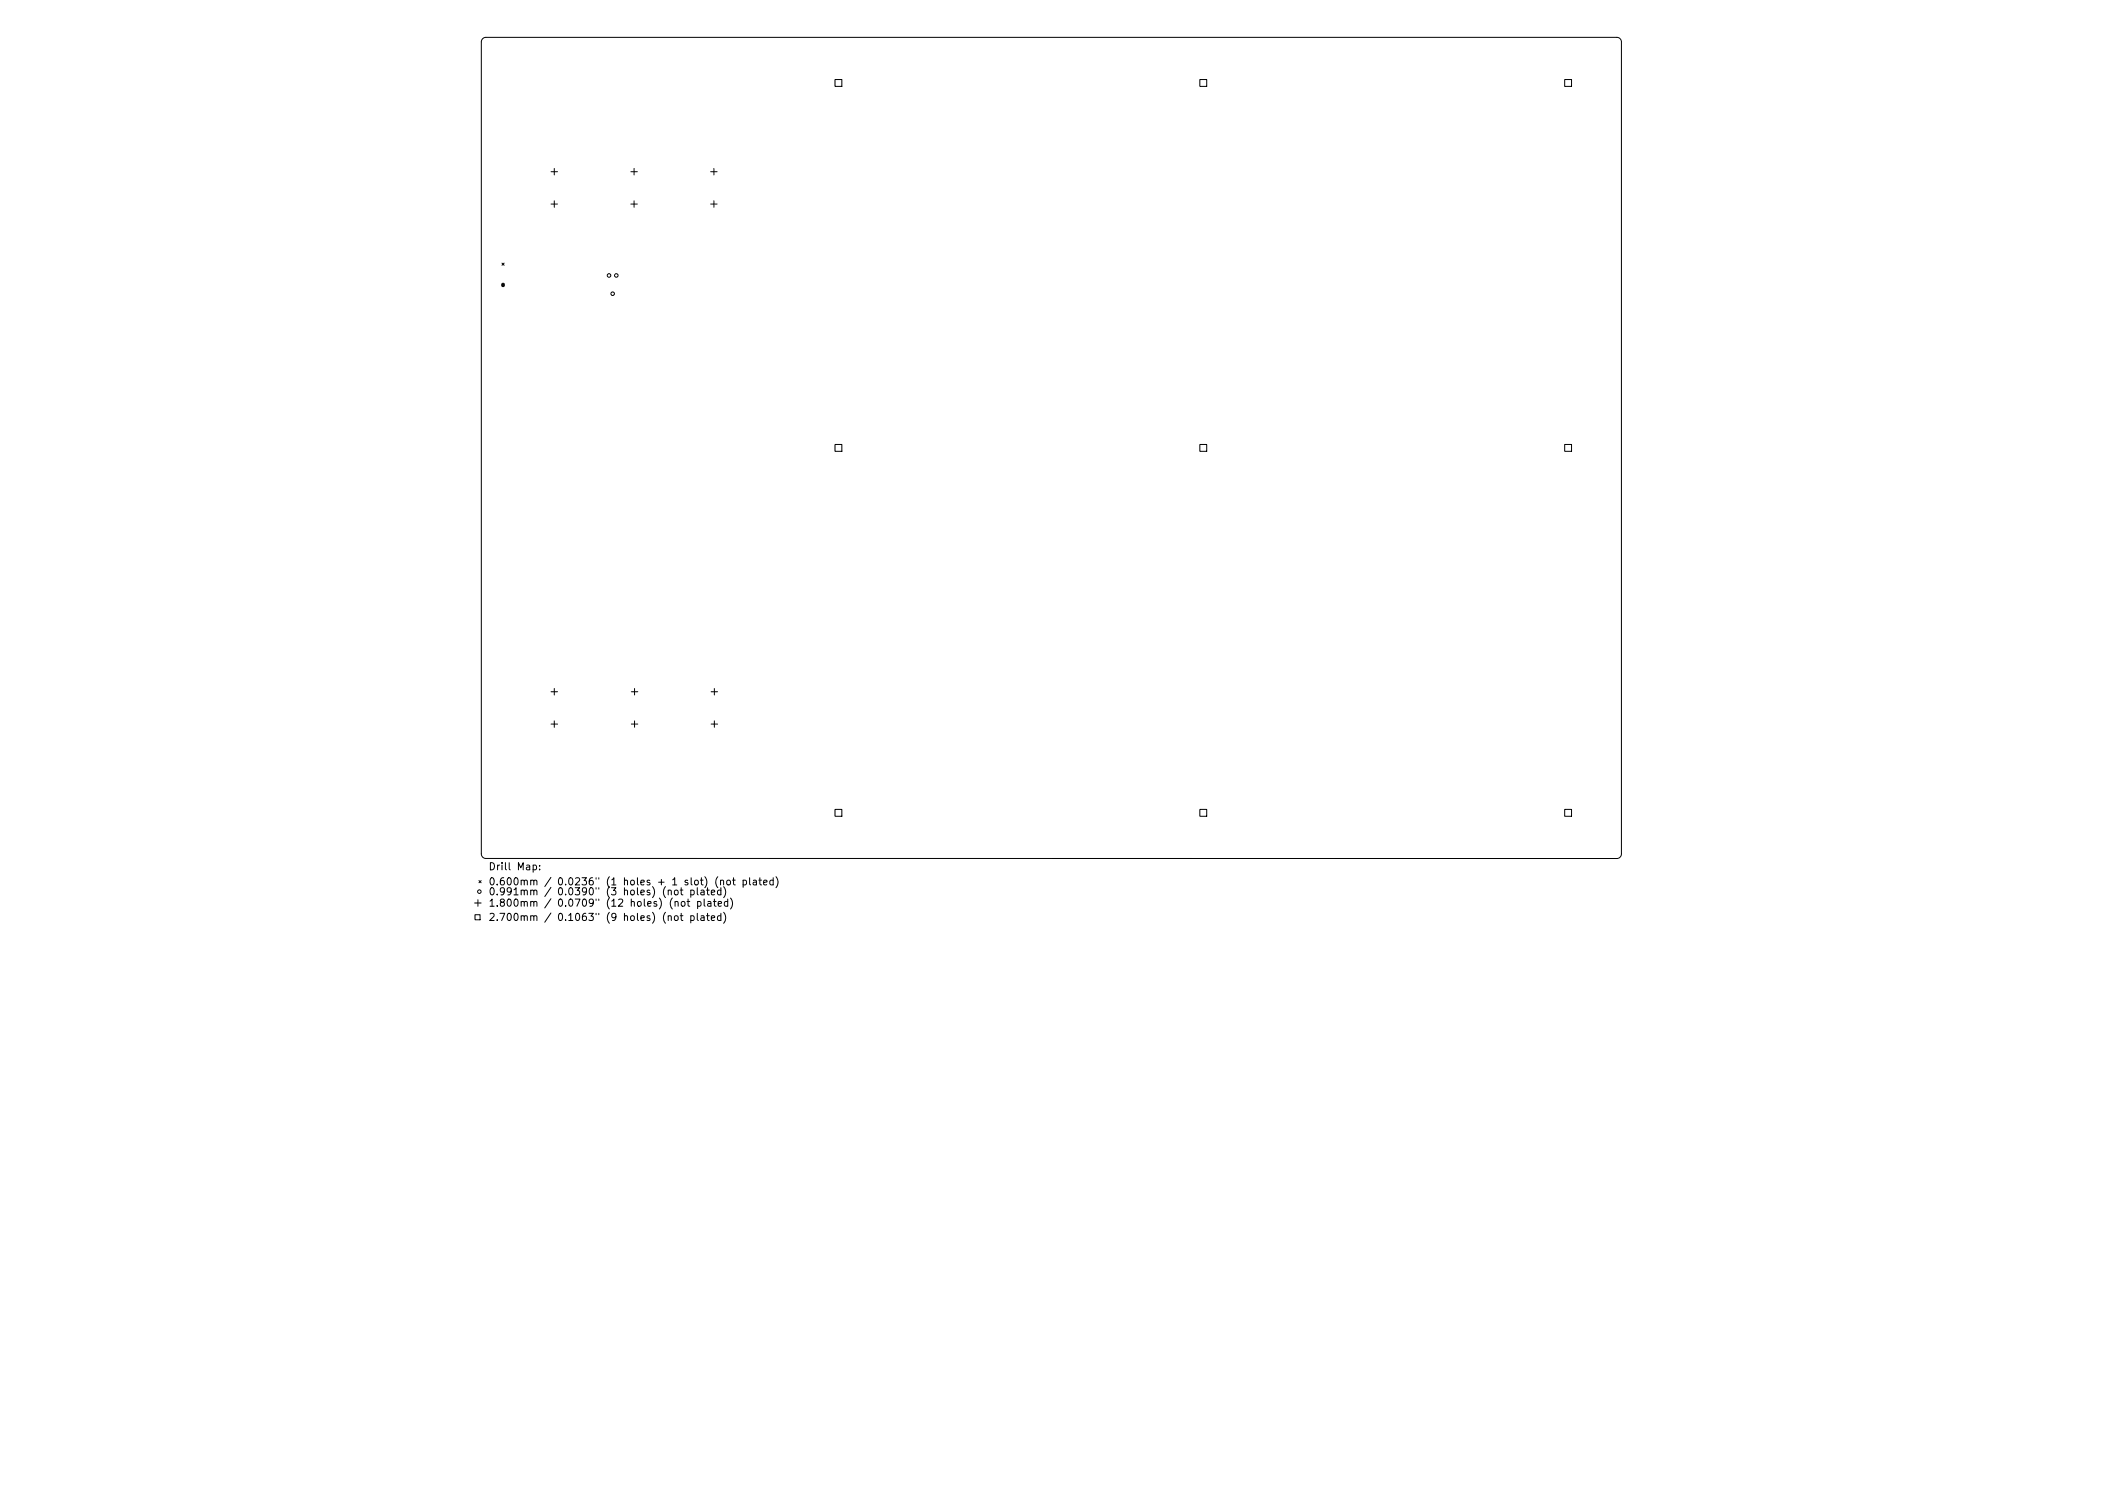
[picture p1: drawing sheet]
<svg xmlns="http://www.w3.org/2000/svg" width="297mm" height="210mm" viewBox="0 0 297 210" stroke-linecap="round" stroke-linejoin="round" font-family="sans-serif">
<defs><g id="words">
<g font-size="1.4">
<text x="69" y="122.9">Drill Map:</text>
<text x="69" y="125">0.600mm / 0.0236&quot; (1 holes + 1 slot) (not plated)</text>
<text x="69" y="126.4">0.991mm / 0.0390&quot; (3 holes) (not plated)</text>
<text x="69" y="128">1.800mm / 0.0709&quot; (12 holes) (not plated)</text>
<text x="69" y="130">2.700mm / 0.1063&quot; (9 holes) (not plated)</text>
</g>
</g></defs>
<g fill="none" stroke="#000" stroke-width=".14">
<path d="M68.2 5.5l.4-.2h159.8a.64 .64 0 0 1 .6 .6v114.7a.65 .65 0 0 1-.6 .6h-159.8a.64 .64 0 0 1-.6-.6v-114.7zM117.9 11.2h1v1h-1zM169.5 11.2h.9v1h-.9zM221 11.2h1v1h-1zM70.9 37.2l.3 .3M71.2 37.2l-.3 .3M77.8 24.2h.9M77.8 28.8h.9M78.3 23.8v.9M78.3 28.4v.9M89.1 24.2h.9M89.1 28.8h.9"/>
<path d="M89.6 23.8v.9M89.6 28.4v.9M100.4 24.2h.9M100.4 28.8h.9M100.8 23.8v.9M100.8 28.4v.9M70.9 40.1l.3 .3M70.9 40l.3 .1-.1 .4-.2-.1zM71.2 40.1l-.3 .3M117.9 62.8h1v.9h-1zM169.5 62.8h.9v.9h-.9zM221 62.8h1v.9h-1z"/>
<path d="M77.8 97.7h.9M78.3 97.2v.9M89.2 97.7h.9M89.6 97.2v.9M100.4 97.7h1M100.9 97.2v.9M77.8 102.2h.9M78.3 101.8v.9M89.2 102.2h.9M89.6 101.8v.9M100.4 102.2h1M100.9 101.8v.9"/>
<path d="M117.9 114.3h1v1h-1zM169.5 114.3h.9v1h-.9zM221 114.3h1v1h-1zM67 127.5h1M67.1 129.2h.7v.7h-.7zM67.5 127.1v.9M67.7 124.3l.3 .4M68 124.3l-.3 .4M75.3 122.2h.3l.2 .1-.1 .5h-.4M76.2 122.7v.1M76.2 122.2v.1M94.4 125.8l.1-.1h.3v.7"/>
<path d="M94.4 129.4l.1-.1 .3 .1v.6M95.3 125.7h.3l.2 .2v.3l-.2 .2-.3-.1v-.1zM95.3 127.4l.2-.1h.2l.1 .7M95.3 129.4l.3-.1 .2 .2v.3l-.2 .2-.3-.1v-.1zM96.1 129.3h.4M96.2 125.3v.9l.3 .2M96.2 129v.8l.3 .2M96.3 127.4l.1-.1 .3 .1 .1 .4-.1 .1-.3 .1-.1-.1zM97 127.3h.4M97.2 127v.8l.2 .2M97.6 125.7h.3l.2 .2-.1 .4h-.4M97.6 129.4l.3-.1 .2 .2-.1 .4h-.4"/>
<path d="M97.6 125.7v1M97.6 129.3v1M98.5 125.3v.9l.1 .2M98.5 129v.8l.1 .2M98.5 127.3h.3l.2 .2-.1 .4h-.4M98.5 127.3v1M99 125.7h.4l.1 .7M99 129.4h.4l.1 .6M99.5 125.9l-.4 .1-.1 .1 .1 .3 .4-.1M99.5 127v.8l.1 .2M99.5 129.5l-.4 .1-.1 .1 .1 .3 .4-.1M99.6 123.8a1.16 1.16 0 0 1 0 1.5"/>
<path d="M99.8 125.7h.4M99.8 129.3h.4M99.9 125.3v.9l.3 .2M99.9 129v.8l.3 .2M100 127.3h.4v.7M100.4 127.5l-.3 .1-.2 .1 .2 .3 .3-.1M100.5 126l.5-.1-.1-.2h-.3l-.1 .1v.5h.4M100.5 129.6l.5-.1-.1-.1-.3-.1-.1 .2v.4h.4M100.8 127.3h.3M100.9 127v.8l.2 .2M101.4 123.8a1.16 1.16 0 0 0 0 1.5M101.4 127.6l.5-.1v-.2h-.3l-.2 .1 .1 .5h.4"/>
<path d="M101.8 124.4l.1-.1h.3v.7M101.8 124.3v.7M101.8 125.7h-.3l-.2 .2 .1 .4h.4M101.8 129.4l-.3-.1-.2 .2 .1 .4h.4M101.8 125.3v1.1M101.8 129v1M102.2 125.2a1.16 1.16 0 0 1 0 1.5M102.2 128.8a1.16 1.16 0 0 1 0 1.6M102.7 124.4l.1-.1 .3 .1 .1 .4-.1 .1-.3 .1-.1-.1zM102.8 127.3h-.3l-.2 .2 .1 .4h.4M102.8 127v1M103.2 126.8a1.16 1.16 0 0 1 0 1.6"/>
<path d="M103.5 124.3h.4M103.6 123.9v.9l.3 .2M105 124.3h.3l.1 .2-.1 .4h-.3M105 124.3v1M105.9 123.9v.9l.1 .2M106.4 124.3h.4v.7M106.8 124.5l-.3 .1-.1 .1 .1 .3 .3-.1M107.2 124.3h.4M107.3 123.9v.9l.3 .2M107.9 124.6l.4-.1v-.2h-.3l-.1 .1v.5h.4M109.2 124.3h-.3l-.2 .2 .1 .4h.4M109.2 123.9v1.1"/>
<path d="M109.6 123.8a1.16 1.16 0 0 1 0 1.5"/>
<circle cx="86" cy="38.9" r=".25"/>
<circle cx="87" cy="38.9" r=".25"/>
<circle cx="86.5" cy="41.5" r=".25"/>
<circle cx="67.7" cy="125.9" r=".25"/>
</g>
<use href="#words"/>
</svg>
